# CLAUDE S81-PH: S81 die PLL RESERVATION abstract (analog hard IP; outline 172.8 x 172.8 um = 0.0299 mm2 ASSUMED,
# pins + PG + obstruction only, no timing claim).  Pins on M4 at the west edge; PG rails on M4 as the SRAM macros.
VERSION 5.7 ;
BUSBITCHARS "[]" ;
DIVIDERCHAR "/" ;
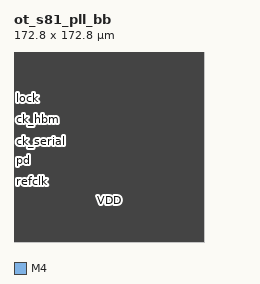
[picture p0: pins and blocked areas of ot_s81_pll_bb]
MACRO ot_s81_pll_bb
  FOREIGN ot_s81_pll_bb 0 0 ;
  SYMMETRY X Y ;
  SIZE 172.800 BY 172.800 ;
  CLASS BLOCK ;
  PIN refclk
    DIRECTION INPUT ;
    USE CLOCK ;
    SHAPE ABUTMENT ;
    PORT
      LAYER M4 ;
      RECT 0.000 62.208 0.024 62.232 ;
    END
  END refclk
  PIN pd
    DIRECTION INPUT ;
    USE SIGNAL ;
    SHAPE ABUTMENT ;
    PORT
      LAYER M4 ;
      RECT 0.000 74.496 0.024 74.520 ;
    END
  END pd
  PIN ck_stream
    DIRECTION OUTPUT ;
    USE CLOCK ;
    SHAPE ABUTMENT ;
    PORT
      LAYER M4 ;
      RECT 0.000 86.784 0.024 86.808 ;
    END
  END ck_stream
  PIN ck_serial
    DIRECTION OUTPUT ;
    USE CLOCK ;
    SHAPE ABUTMENT ;
    PORT
      LAYER M4 ;
      RECT 0.000 99.072 0.024 99.096 ;
    END
  END ck_serial
  PIN ck_hbm
    DIRECTION OUTPUT ;
    USE CLOCK ;
    SHAPE ABUTMENT ;
    PORT
      LAYER M4 ;
      RECT 0.000 111.360 0.024 111.384 ;
    END
  END ck_hbm
  PIN lock
    DIRECTION OUTPUT ;
    USE SIGNAL ;
    SHAPE ABUTMENT ;
    PORT
      LAYER M4 ;
      RECT 0.000 123.648 0.024 123.672 ;
    END
  END lock
  PIN VDD
    DIRECTION INOUT ;
    USE POWER ;
    PORT
      LAYER M4 ;
      RECT 0.300 0.384 172.500 0.480 ;
      RECT 0.300 1.920 172.500 2.016 ;
      RECT 0.300 3.456 172.500 3.552 ;
      RECT 0.300 4.992 172.500 5.088 ;
      RECT 0.300 6.528 172.500 6.624 ;
      RECT 0.300 8.064 172.500 8.160 ;
      RECT 0.300 9.600 172.500 9.696 ;
      RECT 0.300 11.136 172.500 11.232 ;
      RECT 0.300 12.672 172.500 12.768 ;
      RECT 0.300 14.208 172.500 14.304 ;
      RECT 0.300 15.744 172.500 15.840 ;
      RECT 0.300 17.280 172.500 17.376 ;
      RECT 0.300 18.816 172.500 18.912 ;
      RECT 0.300 20.352 172.500 20.448 ;
      RECT 0.300 21.888 172.500 21.984 ;
      RECT 0.300 23.424 172.500 23.520 ;
      RECT 0.300 24.960 172.500 25.056 ;
      RECT 0.300 26.496 172.500 26.592 ;
      RECT 0.300 28.032 172.500 28.128 ;
      RECT 0.300 29.568 172.500 29.664 ;
      RECT 0.300 31.104 172.500 31.200 ;
      RECT 0.300 32.640 172.500 32.736 ;
      RECT 0.300 34.176 172.500 34.272 ;
      RECT 0.300 35.712 172.500 35.808 ;
      RECT 0.300 37.248 172.500 37.344 ;
      RECT 0.300 38.784 172.500 38.880 ;
      RECT 0.300 40.320 172.500 40.416 ;
      RECT 0.300 41.856 172.500 41.952 ;
      RECT 0.300 43.392 172.500 43.488 ;
      RECT 0.300 44.928 172.500 45.024 ;
      RECT 0.300 46.464 172.500 46.560 ;
      RECT 0.300 48.000 172.500 48.096 ;
      RECT 0.300 49.536 172.500 49.632 ;
      RECT 0.300 51.072 172.500 51.168 ;
      RECT 0.300 52.608 172.500 52.704 ;
      RECT 0.300 54.144 172.500 54.240 ;
      RECT 0.300 55.680 172.500 55.776 ;
      RECT 0.300 57.216 172.500 57.312 ;
      RECT 0.300 58.752 172.500 58.848 ;
      RECT 0.300 60.288 172.500 60.384 ;
      RECT 0.300 61.824 172.500 61.920 ;
      RECT 0.300 63.360 172.500 63.456 ;
      RECT 0.300 64.896 172.500 64.992 ;
      RECT 0.300 66.432 172.500 66.528 ;
      RECT 0.300 67.968 172.500 68.064 ;
      RECT 0.300 69.504 172.500 69.600 ;
      RECT 0.300 71.040 172.500 71.136 ;
      RECT 0.300 72.576 172.500 72.672 ;
      RECT 0.300 74.112 172.500 74.208 ;
      RECT 0.300 75.648 172.500 75.744 ;
      RECT 0.300 77.184 172.500 77.280 ;
      RECT 0.300 78.720 172.500 78.816 ;
      RECT 0.300 80.256 172.500 80.352 ;
      RECT 0.300 81.792 172.500 81.888 ;
      RECT 0.300 83.328 172.500 83.424 ;
      RECT 0.300 84.864 172.500 84.960 ;
      RECT 0.300 86.400 172.500 86.496 ;
      RECT 0.300 87.936 172.500 88.032 ;
      RECT 0.300 89.472 172.500 89.568 ;
      RECT 0.300 91.008 172.500 91.104 ;
      RECT 0.300 92.544 172.500 92.640 ;
      RECT 0.300 94.080 172.500 94.176 ;
      RECT 0.300 95.616 172.500 95.712 ;
      RECT 0.300 97.152 172.500 97.248 ;
      RECT 0.300 98.688 172.500 98.784 ;
      RECT 0.300 100.224 172.500 100.320 ;
      RECT 0.300 101.760 172.500 101.856 ;
      RECT 0.300 103.296 172.500 103.392 ;
      RECT 0.300 104.832 172.500 104.928 ;
      RECT 0.300 106.368 172.500 106.464 ;
      RECT 0.300 107.904 172.500 108.000 ;
      RECT 0.300 109.440 172.500 109.536 ;
      RECT 0.300 110.976 172.500 111.072 ;
      RECT 0.300 112.512 172.500 112.608 ;
      RECT 0.300 114.048 172.500 114.144 ;
      RECT 0.300 115.584 172.500 115.680 ;
      RECT 0.300 117.120 172.500 117.216 ;
      RECT 0.300 118.656 172.500 118.752 ;
      RECT 0.300 120.192 172.500 120.288 ;
      RECT 0.300 121.728 172.500 121.824 ;
      RECT 0.300 123.264 172.500 123.360 ;
      RECT 0.300 124.800 172.500 124.896 ;
      RECT 0.300 126.336 172.500 126.432 ;
      RECT 0.300 127.872 172.500 127.968 ;
      RECT 0.300 129.408 172.500 129.504 ;
      RECT 0.300 130.944 172.500 131.040 ;
      RECT 0.300 132.480 172.500 132.576 ;
      RECT 0.300 134.016 172.500 134.112 ;
      RECT 0.300 135.552 172.500 135.648 ;
      RECT 0.300 137.088 172.500 137.184 ;
      RECT 0.300 138.624 172.500 138.720 ;
      RECT 0.300 140.160 172.500 140.256 ;
      RECT 0.300 141.696 172.500 141.792 ;
      RECT 0.300 143.232 172.500 143.328 ;
      RECT 0.300 144.768 172.500 144.864 ;
      RECT 0.300 146.304 172.500 146.400 ;
      RECT 0.300 147.840 172.500 147.936 ;
      RECT 0.300 149.376 172.500 149.472 ;
      RECT 0.300 150.912 172.500 151.008 ;
      RECT 0.300 152.448 172.500 152.544 ;
      RECT 0.300 153.984 172.500 154.080 ;
      RECT 0.300 155.520 172.500 155.616 ;
      RECT 0.300 157.056 172.500 157.152 ;
      RECT 0.300 158.592 172.500 158.688 ;
      RECT 0.300 160.128 172.500 160.224 ;
      RECT 0.300 161.664 172.500 161.760 ;
      RECT 0.300 163.200 172.500 163.296 ;
      RECT 0.300 164.736 172.500 164.832 ;
      RECT 0.300 166.272 172.500 166.368 ;
      RECT 0.300 167.808 172.500 167.904 ;
      RECT 0.300 169.344 172.500 169.440 ;
      RECT 0.300 170.880 172.500 170.976 ;
      RECT 0.300 172.416 172.500 172.512 ;
    END
  END VDD
  PIN VSS
    DIRECTION INOUT ;
    USE GROUND ;
    PORT
      LAYER M4 ;
      RECT 0.300 1.152 172.500 1.248 ;
      RECT 0.300 2.688 172.500 2.784 ;
      RECT 0.300 4.224 172.500 4.320 ;
      RECT 0.300 5.760 172.500 5.856 ;
      RECT 0.300 7.296 172.500 7.392 ;
      RECT 0.300 8.832 172.500 8.928 ;
      RECT 0.300 10.368 172.500 10.464 ;
      RECT 0.300 11.904 172.500 12.000 ;
      RECT 0.300 13.440 172.500 13.536 ;
      RECT 0.300 14.976 172.500 15.072 ;
      RECT 0.300 16.512 172.500 16.608 ;
      RECT 0.300 18.048 172.500 18.144 ;
      RECT 0.300 19.584 172.500 19.680 ;
      RECT 0.300 21.120 172.500 21.216 ;
      RECT 0.300 22.656 172.500 22.752 ;
      RECT 0.300 24.192 172.500 24.288 ;
      RECT 0.300 25.728 172.500 25.824 ;
      RECT 0.300 27.264 172.500 27.360 ;
      RECT 0.300 28.800 172.500 28.896 ;
      RECT 0.300 30.336 172.500 30.432 ;
      RECT 0.300 31.872 172.500 31.968 ;
      RECT 0.300 33.408 172.500 33.504 ;
      RECT 0.300 34.944 172.500 35.040 ;
      RECT 0.300 36.480 172.500 36.576 ;
      RECT 0.300 38.016 172.500 38.112 ;
      RECT 0.300 39.552 172.500 39.648 ;
      RECT 0.300 41.088 172.500 41.184 ;
      RECT 0.300 42.624 172.500 42.720 ;
      RECT 0.300 44.160 172.500 44.256 ;
      RECT 0.300 45.696 172.500 45.792 ;
      RECT 0.300 47.232 172.500 47.328 ;
      RECT 0.300 48.768 172.500 48.864 ;
      RECT 0.300 50.304 172.500 50.400 ;
      RECT 0.300 51.840 172.500 51.936 ;
      RECT 0.300 53.376 172.500 53.472 ;
      RECT 0.300 54.912 172.500 55.008 ;
      RECT 0.300 56.448 172.500 56.544 ;
      RECT 0.300 57.984 172.500 58.080 ;
      RECT 0.300 59.520 172.500 59.616 ;
      RECT 0.300 61.056 172.500 61.152 ;
      RECT 0.300 62.592 172.500 62.688 ;
      RECT 0.300 64.128 172.500 64.224 ;
      RECT 0.300 65.664 172.500 65.760 ;
      RECT 0.300 67.200 172.500 67.296 ;
      RECT 0.300 68.736 172.500 68.832 ;
      RECT 0.300 70.272 172.500 70.368 ;
      RECT 0.300 71.808 172.500 71.904 ;
      RECT 0.300 73.344 172.500 73.440 ;
      RECT 0.300 74.880 172.500 74.976 ;
      RECT 0.300 76.416 172.500 76.512 ;
      RECT 0.300 77.952 172.500 78.048 ;
      RECT 0.300 79.488 172.500 79.584 ;
      RECT 0.300 81.024 172.500 81.120 ;
      RECT 0.300 82.560 172.500 82.656 ;
      RECT 0.300 84.096 172.500 84.192 ;
      RECT 0.300 85.632 172.500 85.728 ;
      RECT 0.300 87.168 172.500 87.264 ;
      RECT 0.300 88.704 172.500 88.800 ;
      RECT 0.300 90.240 172.500 90.336 ;
      RECT 0.300 91.776 172.500 91.872 ;
      RECT 0.300 93.312 172.500 93.408 ;
      RECT 0.300 94.848 172.500 94.944 ;
      RECT 0.300 96.384 172.500 96.480 ;
      RECT 0.300 97.920 172.500 98.016 ;
      RECT 0.300 99.456 172.500 99.552 ;
      RECT 0.300 100.992 172.500 101.088 ;
      RECT 0.300 102.528 172.500 102.624 ;
      RECT 0.300 104.064 172.500 104.160 ;
      RECT 0.300 105.600 172.500 105.696 ;
      RECT 0.300 107.136 172.500 107.232 ;
      RECT 0.300 108.672 172.500 108.768 ;
      RECT 0.300 110.208 172.500 110.304 ;
      RECT 0.300 111.744 172.500 111.840 ;
      RECT 0.300 113.280 172.500 113.376 ;
      RECT 0.300 114.816 172.500 114.912 ;
      RECT 0.300 116.352 172.500 116.448 ;
      RECT 0.300 117.888 172.500 117.984 ;
      RECT 0.300 119.424 172.500 119.520 ;
      RECT 0.300 120.960 172.500 121.056 ;
      RECT 0.300 122.496 172.500 122.592 ;
      RECT 0.300 124.032 172.500 124.128 ;
      RECT 0.300 125.568 172.500 125.664 ;
      RECT 0.300 127.104 172.500 127.200 ;
      RECT 0.300 128.640 172.500 128.736 ;
      RECT 0.300 130.176 172.500 130.272 ;
      RECT 0.300 131.712 172.500 131.808 ;
      RECT 0.300 133.248 172.500 133.344 ;
      RECT 0.300 134.784 172.500 134.880 ;
      RECT 0.300 136.320 172.500 136.416 ;
      RECT 0.300 137.856 172.500 137.952 ;
      RECT 0.300 139.392 172.500 139.488 ;
      RECT 0.300 140.928 172.500 141.024 ;
      RECT 0.300 142.464 172.500 142.560 ;
      RECT 0.300 144.000 172.500 144.096 ;
      RECT 0.300 145.536 172.500 145.632 ;
      RECT 0.300 147.072 172.500 147.168 ;
      RECT 0.300 148.608 172.500 148.704 ;
      RECT 0.300 150.144 172.500 150.240 ;
      RECT 0.300 151.680 172.500 151.776 ;
      RECT 0.300 153.216 172.500 153.312 ;
      RECT 0.300 154.752 172.500 154.848 ;
      RECT 0.300 156.288 172.500 156.384 ;
      RECT 0.300 157.824 172.500 157.920 ;
      RECT 0.300 159.360 172.500 159.456 ;
      RECT 0.300 160.896 172.500 160.992 ;
      RECT 0.300 162.432 172.500 162.528 ;
      RECT 0.300 163.968 172.500 164.064 ;
      RECT 0.300 165.504 172.500 165.600 ;
      RECT 0.300 167.040 172.500 167.136 ;
      RECT 0.300 168.576 172.500 168.672 ;
      RECT 0.300 170.112 172.500 170.208 ;
      RECT 0.300 171.648 172.500 171.744 ;
    END
  END VSS
  OBS
    LAYER M1 ;
    RECT 0 0 172.800 172.800 ;
    LAYER M2 ;
    RECT 0 0 172.800 172.800 ;
    LAYER M3 ;
    RECT 0 0 172.800 172.800 ;
    LAYER M4 ;
    RECT 0.072 0 172.728 172.800 ;
  END
END ot_s81_pll_bb

END LIBRARY
